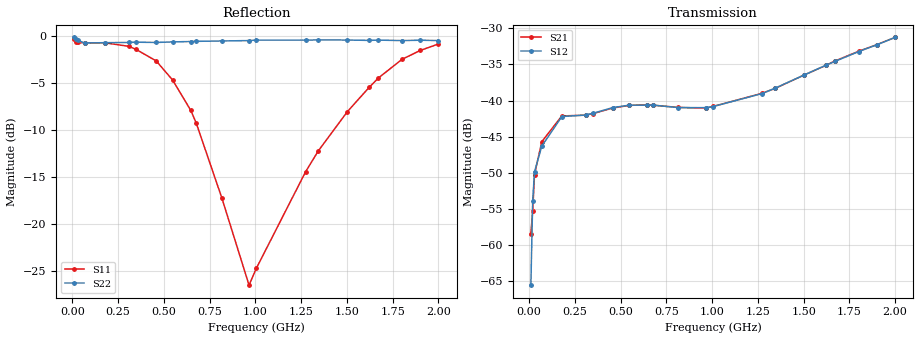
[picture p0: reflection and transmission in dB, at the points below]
!Agilent Technologies,E8364B,MY43040703,A.07.50.48
!Agilent E8364B: A.07.50.48
!Date: Friday, November 12, 2021 03:09:04
!Correction: S11(Full 2 Port(1,2))
!S21(Full 2 Port(1,2))
!S12(Full 2 Port(1,2))
!S22(Full 2 Port(1,2))
!S2P File: Measurements: S11, S21, S12, S22:
# Hz S  dB  R 50
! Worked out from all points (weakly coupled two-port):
!   201 points, 10 MHz to 2 GHz, reference 50 ohm
!   highest |S21| = -31.25 dB at 2 GHz (marker M1); lowest = -58.4 dB at 10 MHz (marker M2)
!   lowest |S11| = -26.5 dB at 965.2 MHz (marker M3), VSWR 1.10, Z = 52.6 + j4.11 ohm
!   |S11| at or under -10 dB: 692.6 MHz to 1.431 GHz (738.1 MHz wide, 69.5 % of centre)
!   |S22| runs from -0.8 to -0.1 dB; largest |S21 - S12| = 0.0017
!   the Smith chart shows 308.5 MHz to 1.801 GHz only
!   S11 on the Smith chart (normalised r, x): 308.5 MHz: 0.28, +1.86; 457.8 MHz: 3.83, -3.21; 646.8 MHz: 0.61, -0.57; 1.274 GHz: 0.81, -0.29; 1.622 GHz: 0.53, +0.79; 1.801 GHz: 4.95, +3.19
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1e7  -0.30 -56.9  -58.38 -5.7  -65.52 155.3  -0.14 -32.7
1.995e7  -0.60 -96.3  -55.29 95.5  -53.83 88.1  -0.33 -60.9
2.99e7  -0.67 -122.7  -50.22 74.9  -49.84 75.8  -0.47 -83.7
6.97e7  -0.73 -175.4  -45.68 28.9  -46.29 28.5  -0.74 -136.1
1.7915e8  -0.72 118.4  -42.12 -24.1  -42.20 -24.0  -0.70 171.1
3.085e8  -1.09 55.7  -42.01 -68.2  -41.99 -68.1  -0.68 137.7
3.483e8  -1.42 36.9  -41.80 -81.5  -41.76 -80.7  -0.65 128.7
4.5775e8  -2.64 -15.0  -41.02 -116.9  -40.96 -116.7  -0.68 105.8
5.473e8  -4.66 -58.2  -40.66 -147.4  -40.63 -147.6  -0.62 88.0
6.468e8  -7.90 -104.4  -40.57 180.0  -40.63 179.6  -0.58 68.7
6.7665e8  -9.25 -118.4  -40.63 170.1  -40.62 169.5  -0.56 63.1
8.1595e8  -17.17 176.5  -40.94 128.6  -40.96 128.3  -0.52 36.8
9.652e8  -26.47 55.1  -41.04 88.1  -40.97 88.2  -0.48 9.3
1.005e9  -24.69 13.3  -40.81 77.4  -40.82 77.4  -0.43 2.0
1.27365e9  -14.44 -113.9  -38.98 5.1  -39.02 5.1  -0.43 -47.1
1.3433e9  -12.21 -142.7  -38.32 -14.1  -38.29 -14.6  -0.41 -59.8
1.5025e9  -8.03 147.9  -36.46 -62.9  -36.46 -62.9  -0.42 -89.0
1.6219e9  -5.44 93.5  -35.12 -101.8  -35.10 -101.6  -0.46 -110.6
1.67165e9  -4.46 70.9  -34.51 -118.3  -34.57 -118.4  -0.43 -119.7
1.801e9  -2.47 10.7  -33.17 -163.0  -33.21 -163.0  -0.48 -143.1
1.9005e9  -1.53 -35.8  -32.25 161.0  -32.27 161.4  -0.44 -161.0
2e9  -0.84 -82.6  -31.25 124.3  -31.25 124.2  -0.48 -179.0
